VERSION 5.7 ;
  NOWIREEXTENSIONATPIN ON ;
  DIVIDERCHAR "/" ;
  BUSBITCHARS "[]" ;
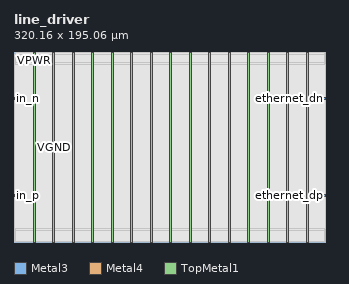
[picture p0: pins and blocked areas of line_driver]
MACRO line_driver
  CLASS BLOCK ;
  FOREIGN line_driver ;
  ORIGIN 0.000 0.000 ;
  SIZE 320.160 BY 195.060 ;
  PIN ethernet_dn
    DIRECTION INOUT ;
    USE SIGNAL ;
    ANTENNADIFFAREA 636.000000 ;
    PORT
      LAYER Metal3 ;
        RECT 318.190 146.470 320.160 148.470 ;
    END
  END ethernet_dn
  PIN ethernet_dp
    DIRECTION INOUT ;
    USE SIGNAL ;
    ANTENNADIFFAREA 636.000000 ;
    PORT
      LAYER Metal3 ;
        RECT 318.190 46.510 320.160 48.510 ;
    END
  END ethernet_dp
  PIN in_n
    DIRECTION INPUT ;
    USE SIGNAL ;
    ANTENNAGATEAREA 12000.000000 ;
    PORT
      LAYER Metal4 ;
        RECT 0.000 146.470 3.000 148.470 ;
    END
  END in_n
  PIN in_p
    DIRECTION INPUT ;
    USE SIGNAL ;
    ANTENNAGATEAREA 12000.000000 ;
    PORT
      LAYER Metal4 ;
        RECT 0.000 46.510 3.000 48.510 ;
    END
  END in_p
  PIN VGND
    DIRECTION INOUT ;
    USE GROUND ;
    PORT
      LAYER TopMetal1 ;
        RECT 40.000 0.000 42.000 195.060 ;
    END
    PORT
      LAYER TopMetal1 ;
        RECT 80.000 0.000 82.000 195.060 ;
    END
    PORT
      LAYER TopMetal1 ;
        RECT 120.000 0.000 122.000 195.060 ;
    END
    PORT
      LAYER TopMetal1 ;
        RECT 160.000 0.000 162.000 195.060 ;
    END
    PORT
      LAYER TopMetal1 ;
        RECT 200.000 0.000 202.000 195.060 ;
    END
    PORT
      LAYER TopMetal1 ;
        RECT 240.000 0.000 242.000 195.060 ;
    END
    PORT
      LAYER TopMetal1 ;
        RECT 280.000 0.000 282.000 195.060 ;
    END
  END VGND
  PIN VPWR
    DIRECTION INOUT ;
    USE POWER ;
    PORT
      LAYER TopMetal1 ;
        RECT 20.000 0.000 22.000 195.060 ;
    END
    PORT
      LAYER TopMetal1 ;
        RECT 60.000 0.000 62.000 195.060 ;
    END
    PORT
      LAYER TopMetal1 ;
        RECT 100.000 0.000 102.000 195.060 ;
    END
    PORT
      LAYER TopMetal1 ;
        RECT 140.000 0.000 142.000 195.060 ;
    END
    PORT
      LAYER TopMetal1 ;
        RECT 180.000 0.000 182.000 195.060 ;
    END
    PORT
      LAYER TopMetal1 ;
        RECT 220.000 0.000 222.000 195.060 ;
    END
    PORT
      LAYER TopMetal1 ;
        RECT 260.000 0.000 262.000 195.060 ;
    END
    PORT
      LAYER TopMetal1 ;
        RECT 300.000 0.000 302.000 195.060 ;
    END
  END VPWR
  OBS
      LAYER GatPoly ;
        RECT 2.000 0.240 318.160 194.820 ;
      LAYER Metal1 ;
        RECT 1.890 0.380 318.270 194.680 ;
      LAYER Metal2 ;
        RECT 1.015 0.340 318.270 192.740 ;
      LAYER Metal3 ;
        RECT 1.890 148.680 318.270 192.740 ;
        RECT 1.890 146.260 317.980 148.680 ;
        RECT 1.890 48.720 318.270 146.260 ;
        RECT 1.890 46.300 317.980 48.720 ;
        RECT 1.890 0.340 318.270 46.300 ;
      LAYER Metal4 ;
        RECT 1.890 148.680 318.270 183.980 ;
        RECT 3.210 146.260 318.270 148.680 ;
        RECT 1.890 48.720 318.270 146.260 ;
        RECT 3.210 46.300 318.270 48.720 ;
        RECT 1.890 11.380 318.270 46.300 ;
      LAYER Metal5 ;
        RECT 0.000 13.380 320.160 181.980 ;
  END
END line_driver
END LIBRARY

